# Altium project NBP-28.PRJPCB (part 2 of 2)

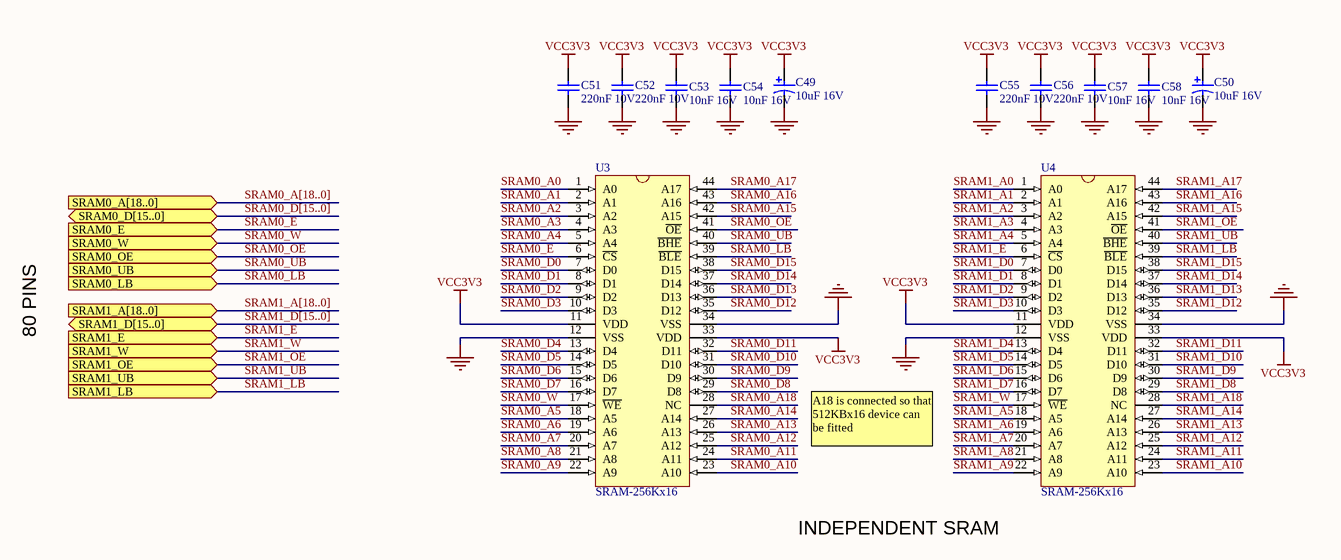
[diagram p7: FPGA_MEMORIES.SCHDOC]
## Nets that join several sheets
+5V: TOP_SHEET (6 pins), FPGA (HDR1.97 HDR1.99 HDR2.97 HDR2.99)
GND: TOP_SHEET (14 pins), PROCESSOR (71 pins), PROCESSOR_MEMORIES (38 pins), FPGA (112 pins), FPGA_MEMORIES (14 pins)
VCC1V2: TOP_SHEET (5 pins), FPGA (26 pins)
VCC1V8: TOP_SHEET (C132.1 C133.1), PROCESSOR (22 pins), FPGA (5 pins)
VCC2V5: TOP_SHEET (8 pins), FPGA (18 pins)
VCC3V3: TOP_SHEET (C126.1 C127.1), PROCESSOR (74 pins), PROCESSOR_MEMORIES (37 pins), FPGA (77 pins), FPGA_MEMORIES (14 pins)
A0: PROCESSOR (U5.32), PROCESSOR_MEMORIES (U7.H7 U9.H7), FPGA (U1.F19)
A1: PROCESSOR (U5.31), PROCESSOR_MEMORIES (U7.H8 U8.G2 U9.H8), FPGA (U1.R18)
A2: PROCESSOR (U5.30), PROCESSOR_MEMORIES (U7.J8 U8.F2 U9.J8), FPGA (U1.T22)
A3: PROCESSOR (U5.29), PROCESSOR_MEMORIES (U7.J7 U8.E2 U9.J7), FPGA (U1.R21)
A4: PROCESSOR (U5.27), PROCESSOR_MEMORIES (U7.J3 U8.C2 U9.J3), FPGA (U1.M22)
A5: PROCESSOR (U5.26), PROCESSOR_MEMORIES (U7.J2 U8.D2 U9.J2), FPGA (U1.N21)
A6: PROCESSOR (U5.25), PROCESSOR_MEMORIES (U7.H3 U8.F3 U9.H3), FPGA (U1.L17)
A7: PROCESSOR (U5.24), PROCESSOR_MEMORIES (U7.H2 U8.E3 U9.H2), FPGA (U1.N22)
A8: PROCESSOR (U5.22), PROCESSOR_MEMORIES (U7.H1 U8.C3 U9.H1), FPGA (U1.J17)
A9: PROCESSOR (U5.21), PROCESSOR_MEMORIES (U7.G3 U8.D6 U9.G3), FPGA (U1.K17)
A10: PROCESSOR (U5.20), PROCESSOR_MEMORIES (U7.H9 U8.C6 U9.H9), FPGA (U1.P21)
A11: PROCESSOR (U5.19), PROCESSOR_MEMORIES (U7.G2 U8.E6 U9.G2), FPGA (U1.P17)
A12: PROCESSOR (U5.17), PROCESSOR_MEMORIES (U7.G1 U8.F6 U9.G1), FPGA (U1.T17)
A13: PROCESSOR (U5.16), PROCESSOR_MEMORIES (U7.G7 U8.D7 U9.G7), FPGA (U1.N17)
A14: PROCESSOR (U5.15), PROCESSOR_MEMORIES (U7.G8 U8.C7 U9.G8), FPGA (U1.M17)
A15: PROCESSOR (U5.14), PROCESSOR_MEMORIES (U8.E7), FPGA (U1.T18)
A16: PROCESSOR (U5.12), PROCESSOR_MEMORIES (U8.F7), FPGA (U1.U18)
A17: PROCESSOR (U5.11), PROCESSOR_MEMORIES (U8.G7), FPGA (U1.U17)
A18: PROCESSOR (U5.10), PROCESSOR_MEMORIES (U8.D3), FPGA (U1.P22)
A19: PROCESSOR (U5.9), PROCESSOR_MEMORIES (U8.E4), FPGA (U1.R22)
A20: PROCESSOR (U5.7), PROCESSOR_MEMORIES (U8.F5), FPGA (U1.T21)
A21: PROCESSOR (U5.6), PROCESSOR_MEMORIES (U8.F4), FPGA (U1.G17)
A22: PROCESSOR (U5.5), PROCESSOR_MEMORIES (U8.E5), FPGA (U1.F21)
A23: PROCESSOR (U5.4), FPGA (U1.E22)
A24: PROCESSOR (U5.3), FPGA (U1.E21)
A25: PROCESSOR (U5.2), FPGA (U1.D22)
CLK_RTC: PROCESSOR (R44.2), FPGA (U1.G19)
CLKIN: PROCESSOR (R36.2), FPGA (U1.G20)
CLKOUT: PROCESSOR (U5.156), FPGA (U1.C12)
D0: PROCESSOR (U5.87), PROCESSOR_MEMORIES (U8.G3 U9.A8), FPGA (U1.AA17)
D1: PROCESSOR (U5.86), PROCESSOR_MEMORIES (U8.K3 U9.B9), FPGA (U1.Y21)
D2: PROCESSOR (U5.84), PROCESSOR_MEMORIES (U8.G4 U9.B8), FPGA (U1.U21)
D3: PROCESSOR (U5.83), PROCESSOR_MEMORIES (U8.K4 U9.C9), FPGA (U1.Y22)
D4: PROCESSOR (U5.82), PROCESSOR_MEMORIES (U8.K5 U9.C8), FPGA (U1.W21)
D5: PROCESSOR (U5.81), PROCESSOR_MEMORIES (U8.G5 U9.D9), FPGA (U1.U16)
D6: PROCESSOR (U5.79), PROCESSOR_MEMORIES (U8.K6 U9.D8), FPGA (U1.W22)
D7: PROCESSOR (U5.78), PROCESSOR_MEMORIES (U8.G6 U9.E9), FPGA (U1.V21)
D8: PROCESSOR (U5.77), PROCESSOR_MEMORIES (U8.H3 U9.E1), FPGA (U1.V18)
D9: PROCESSOR (U5.76), PROCESSOR_MEMORIES (U8.J3 U9.D2), FPGA (U1.AA20)
D10: PROCESSOR (U5.74), PROCESSOR_MEMORIES (U8.H4 U9.D1), FPGA (U1.V22)
D11: PROCESSOR (U5.73), PROCESSOR_MEMORIES (U8.J4 U9.C2), FPGA (U1.AB20)
D12: PROCESSOR (U5.72), PROCESSOR_MEMORIES (U8.H5 U9.C1), FPGA (U1.AB18)
D13: PROCESSOR (U5.71), PROCESSOR_MEMORIES (U8.J6 U9.B2), FPGA (U1.AA19)
D14: PROCESSOR (U5.69), PROCESSOR_MEMORIES (U8.H6 U9.B1), FPGA (U1.AA18)
D15: PROCESSOR (U5.68), PROCESSOR_MEMORIES (U8.J7 U9.A2), FPGA (U1.AB19)
D16: PROCESSOR (U5.67), PROCESSOR_MEMORIES (U7.A8), FPGA (U1.V7)
D17: PROCESSOR (U5.66), PROCESSOR_MEMORIES (U7.B9), FPGA (U1.V9)
D18: PROCESSOR (U5.65), PROCESSOR_MEMORIES (U7.B8), FPGA (U1.V10)
D19: PROCESSOR (U5.63), PROCESSOR_MEMORIES (U7.C9), FPGA (U1.V6)
D20: PROCESSOR (U5.62), PROCESSOR_MEMORIES (U7.C8), FPGA (U1.V11)
D21: PROCESSOR (U5.61), PROCESSOR_MEMORIES (U7.D9), FPGA (U1.U6)
D22: PROCESSOR (U5.60), PROCESSOR_MEMORIES (U7.D8), FPGA (U1.V8)
D23: PROCESSOR (U5.59), PROCESSOR_MEMORIES (U7.E9), FPGA (U1.V5)
D24: PROCESSOR (U5.58), PROCESSOR_MEMORIES (U7.E1), FPGA (U1.U13)
D25: PROCESSOR (U5.57), PROCESSOR_MEMORIES (U7.D2), FPGA (U1.U14)
D26: PROCESSOR (U5.56), PROCESSOR_MEMORIES (U7.D1), FPGA (U1.V17)
D27: PROCESSOR (U5.54), PROCESSOR_MEMORIES (U7.C2), FPGA (U1.V16)
D28: PROCESSOR (U5.53), PROCESSOR_MEMORIES (U7.C1), FPGA (U1.V15)
D29: PROCESSOR (U5.52), PROCESSOR_MEMORIES (U7.B2), FPGA (U1.V14)
D30: PROCESSOR (U5.51), PROCESSOR_MEMORIES (U7.B1), FPGA (U1.V13)
D31: PROCESSOR (U5.50), PROCESSOR_MEMORIES (U7.A2), FPGA (U1.U12)
DEOT0: PROCESSOR (U5.148), FPGA (U1.L18)
DREQ0: PROCESSOR (U5.146), FPGA (U1.M18)
FLASH_BUSY: PROCESSOR (R20.1 U5.114), PROCESSOR_MEMORIES (U8.C4)
FPGA_TCK: PROCESSOR (U6.11), FPGA (HDR1.72 R12.1)
FPGA_TMS: PROCESSOR (U6.14), FPGA (HDR1.70 R13.1)
INT0: PROCESSOR (U5.155), FPGA (U1.B19)
INT1: PROCESSOR (U5.153), FPGA (U1.B20)
INT2: PROCESSOR (U5.152), FPGA (U1.C21)
INT3: PROCESSOR (U5.151), FPGA (U1.C22)
INT4: PROCESSOR (U5.150), FPGA (U1.D21)
nBLE0: PROCESSOR (U5.37), FPGA (U1.H22)
nBLE1: PROCESSOR (U5.36), FPGA (U1.H21)
nBLE2: PROCESSOR (U5.35), FPGA (U1.G22)
nBLE3: PROCESSOR (U5.34), FPGA (U1.G21)
nCS0: PROCESSOR (U5.48), FPGA (U1.L21)
nCS1: PROCESSOR (U5.47), FPGA (U1.L22)
nCS2: PROCESSOR (U5.46), FPGA (U1.M21)
nCS3: PROCESSOR (U5.44), FPGA (U1.K22)
nCS4: PROCESSOR (U5.43), FPGA (U1.K21)
nCS5: PROCESSOR (U5.42), FPGA (U1.J22)
nDACK0: PROCESSOR (U5.147), FPGA (U1.N18)
nFLASH_CS: PROCESSOR (U5.41), PROCESSOR_MEMORIES (U8.H2)
nOE: PROCESSOR (U5.38), PROCESSOR_MEMORIES (U8.J2), FPGA (U1.J21)
nRESETIN: PROCESSOR (P2.15 R24.1 U5.96), FPGA (U1.H19)
nRESETOUT: PROCESSOR (U5.97), PROCESSOR_MEMORIES (U8.D5), FPGA (U1.F17)
nSDRAM_CAS: PROCESSOR (U5.108), PROCESSOR_MEMORIES (U7.F7 U9.F7)
nSDRAM_CS: PROCESSOR (U5.105), PROCESSOR_MEMORIES (U7.G9 U9.G9)
nSDRAM_RAS: PROCESSOR (U5.107), PROCESSOR_MEMORIES (U7.F8 U9.F8)
nSDRAM_WE: PROCESSOR (U5.106), PROCESSOR_MEMORIES (U7.F9 U9.F9)
nWAIT: PROCESSOR (U5.144), FPGA (U1.P18)
nWE: PROCESSOR (U5.39), PROCESSOR_MEMORIES (U8.C5), FPGA (U1.F16)
PROCESSOR_TDI: PROCESSOR (U6.3 U6.5), FPGA (R1.2 U1.B22)
PROCESSOR_TDO: PROCESSOR (U6.4), FPGA (R6.1)
SDRAM_CKE: PROCESSOR (U5.102), PROCESSOR_MEMORIES (U7.F3 U9.F3)
SDRAM_CLK: PROCESSOR (U5.101), PROCESSOR_MEMORIES (U7.F2 U9.F2)
SDRAM_DQM0: PROCESSOR (U5.112), PROCESSOR_MEMORIES (U9.E8)
SDRAM_DQM1: PROCESSOR (U5.111), PROCESSOR_MEMORIES (U9.F1)
SDRAM_DQM2: PROCESSOR (U5.110), PROCESSOR_MEMORIES (U7.E8)
SDRAM_DQM3: PROCESSOR (U5.109), PROCESSOR_MEMORIES (U7.F1)
SRAM0_A0: FPGA (U1.A13), FPGA_MEMORIES (U3.1)
SRAM0_A1: FPGA (U1.B13), FPGA_MEMORIES (U3.2)
SRAM0_A2: FPGA (U1.A14), FPGA_MEMORIES (U3.3)
SRAM0_A3: FPGA (U1.B14), FPGA_MEMORIES (U3.4)
SRAM0_A4: FPGA (U1.A15), FPGA_MEMORIES (U3.5)
SRAM0_A5: FPGA (U1.B7), FPGA_MEMORIES (U3.18)
SRAM0_A6: FPGA (U1.A7), FPGA_MEMORIES (U3.19)
SRAM0_A7: FPGA (U1.B6), FPGA_MEMORIES (U3.20)
SRAM0_A8: FPGA (U1.B5), FPGA_MEMORIES (U3.21)
SRAM0_A9: FPGA (U1.A5), FPGA_MEMORIES (U3.22)
SRAM0_A10: FPGA (U1.B4), FPGA_MEMORIES (U3.23)
SRAM0_A11: FPGA (U1.A4), FPGA_MEMORIES (U3.24)
SRAM0_A12: FPGA (U1.A3), FPGA_MEMORIES (U3.25)
SRAM0_A13: FPGA (U1.C2), FPGA_MEMORIES (U3.26)
SRAM0_A14: FPGA (U1.C1), FPGA_MEMORIES (U3.27)
SRAM0_A15: FPGA (U1.K1), FPGA_MEMORIES (U3.42)
SRAM0_A16: FPGA (U1.L2), FPGA_MEMORIES (U3.43)
SRAM0_A17: FPGA (U1.L1), FPGA_MEMORIES (U3.44)
SRAM0_A18: FPGA (U1.D2), FPGA_MEMORIES (U3.28)
SRAM0_D0: FPGA (U1.A12), FPGA_MEMORIES (U3.7)
SRAM0_D1: FPGA (U1.B11), FPGA_MEMORIES (U3.8)
SRAM0_D2: FPGA (U1.A11), FPGA_MEMORIES (U3.9)
SRAM0_D3: FPGA (U1.B10), FPGA_MEMORIES (U3.10)
SRAM0_D4: FPGA (U1.A10), FPGA_MEMORIES (U3.13)
SRAM0_D5: FPGA (U1.B9), FPGA_MEMORIES (U3.14)
SRAM0_D6: FPGA (U1.A9), FPGA_MEMORIES (U3.15)
SRAM0_D7: FPGA (U1.B8), FPGA_MEMORIES (U3.16)
SRAM0_D8: FPGA (U1.D1), FPGA_MEMORIES (U3.29)
SRAM0_D9: FPGA (U1.E2), FPGA_MEMORIES (U3.30)
SRAM0_D10: FPGA (U1.E1), FPGA_MEMORIES (U3.31)
SRAM0_D11: FPGA (U1.F2), FPGA_MEMORIES (U3.32)
SRAM0_D12: FPGA (U1.G2), FPGA_MEMORIES (U3.35)
SRAM0_D13: FPGA (U1.G1), FPGA_MEMORIES (U3.36)
SRAM0_D14: FPGA (U1.H2), FPGA_MEMORIES (U3.37)
SRAM0_D15: FPGA (U1.H1), FPGA_MEMORIES (U3.38)
SRAM0_E: FPGA (U1.B12), FPGA_MEMORIES (U3.6)
SRAM0_LB: FPGA (U1.J2), FPGA_MEMORIES (U3.39)
SRAM0_OE: FPGA (U1.K2), FPGA_MEMORIES (U3.41)
SRAM0_UB: FPGA (U1.J1), FPGA_MEMORIES (U3.40)
SRAM0_W: FPGA (U1.A8), FPGA_MEMORIES (U3.17)
SRAM1_A0: FPGA (U1.Y12), FPGA_MEMORIES (U4.1)
SRAM1_A1: FPGA (R19.2 U1.W12), FPGA_MEMORIES (U4.2)
SRAM1_A2: FPGA (U1.N1), FPGA_MEMORIES (U4.3)
SRAM1_A3: FPGA (U1.N2), FPGA_MEMORIES (U4.4)
SRAM1_A4: FPGA (U1.P1), FPGA_MEMORIES (U4.5)
SRAM1_A5: FPGA (U1.Y1), FPGA_MEMORIES (U4.18)
SRAM1_A6: FPGA (U1.Y2), FPGA_MEMORIES (U4.19)
SRAM1_A7: FPGA (U1.AA3), FPGA_MEMORIES (U4.20)
SRAM1_A8: FPGA (U1.AB4), FPGA_MEMORIES (U4.21)
SRAM1_A9: FPGA (U1.AA4), FPGA_MEMORIES (U4.22)
SRAM1_A10: FPGA (U1.AB5), FPGA_MEMORIES (U4.23)
SRAM1_A11: FPGA (U1.AA5), FPGA_MEMORIES (U4.24)
SRAM1_A12: FPGA (U1.AA6), FPGA_MEMORIES (U4.25)
SRAM1_A13: FPGA (U1.AB7), FPGA_MEMORIES (U4.26)
SRAM1_A14: FPGA (U1.AA7), FPGA_MEMORIES (U4.27)
SRAM1_A15: FPGA (U1.AA12), FPGA_MEMORIES (U4.42)
SRAM1_A16: FPGA (U1.AB11), FPGA_MEMORIES (U4.43)
SRAM1_A17: FPGA (U1.AA10), FPGA_MEMORIES (U4.44)
SRAM1_A18: FPGA (U1.AB8), FPGA_MEMORIES (U4.28)
SRAM1_D0: FPGA (U1.R1), FPGA_MEMORIES (U4.7)
SRAM1_D1: FPGA (U1.R2), FPGA_MEMORIES (U4.8)
SRAM1_D2: FPGA (U1.T1), FPGA_MEMORIES (U4.9)
SRAM1_D3: FPGA (U1.T2), FPGA_MEMORIES (U4.10)
SRAM1_D4: FPGA (U1.U2), FPGA_MEMORIES (U4.13)
SRAM1_D5: FPGA (U1.V1), FPGA_MEMORIES (U4.14)
SRAM1_D6: FPGA (U1.V2), FPGA_MEMORIES (U4.15)
SRAM1_D7: FPGA (U1.W1), FPGA_MEMORIES (U4.16)
SRAM1_D8: FPGA (U1.AA8), FPGA_MEMORIES (U4.29)
SRAM1_D9: FPGA (U1.AB9), FPGA_MEMORIES (U4.30)
SRAM1_D10: FPGA (U1.AA9), FPGA_MEMORIES (U4.31)
SRAM1_D11: FPGA (U1.AB10), FPGA_MEMORIES (U4.32)
SRAM1_D12: FPGA (U1.AA16), FPGA_MEMORIES (U4.35)
SRAM1_D13: FPGA (U1.AB16), FPGA_MEMORIES (U4.36)
SRAM1_D14: FPGA (U1.AA15), FPGA_MEMORIES (U4.37)
SRAM1_D15: FPGA (U1.AB15), FPGA_MEMORIES (U4.38)
SRAM1_E: FPGA (U1.P2), FPGA_MEMORIES (U4.6)
SRAM1_LB: FPGA (U1.AB14), FPGA_MEMORIES (U4.39)
SRAM1_OE: FPGA (U1.AB13), FPGA_MEMORIES (U4.41)
SRAM1_UB: FPGA (U1.AA13), FPGA_MEMORIES (U4.40)
SRAM1_W: FPGA (U1.W2), FPGA_MEMORIES (U4.17)
SSPCLK: PROCESSOR (U5.165), FPGA (U1.B17)
SSPEN: PROCESSOR (U5.166), FPGA (U1.A18)
SSPFRM: PROCESSOR (U5.164), FPGA (U1.B16)
SSPRX_UART2RX: PROCESSOR (U5.169), FPGA (U1.A19)
SSPTX_UART2TX: PROCESSOR (U5.167), FPGA (U1.B18)

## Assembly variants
NBP-28 - Modification_080506: not fitted R23 R36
